VERSION 5.7 ;
  NOWIREEXTENSIONATPIN ON ;
  DIVIDERCHAR "/" ;
  BUSBITCHARS "[]" ;
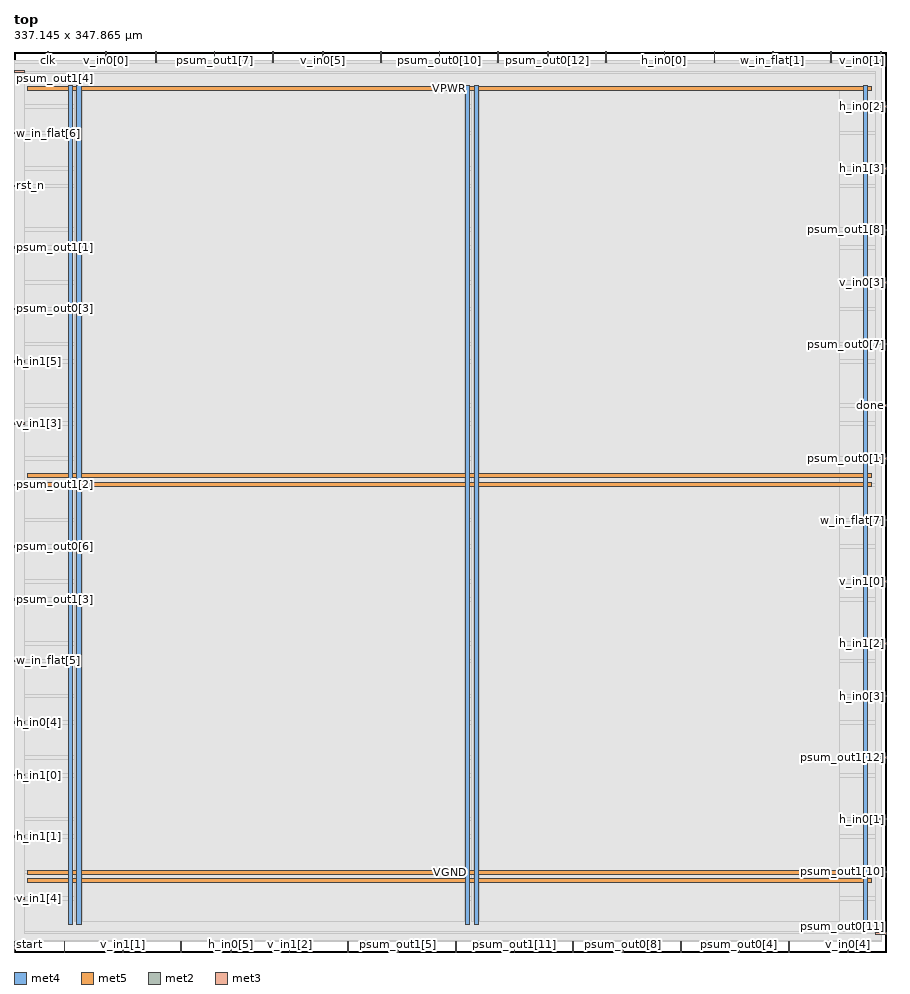
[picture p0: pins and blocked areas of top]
MACRO top
  CLASS BLOCK ;
  FOREIGN top ;
  ORIGIN 0.000 0.000 ;
  SIZE 337.145 BY 347.865 ;
  PIN VGND
    DIRECTION INOUT ;
    USE GROUND ;
    PORT
      LAYER met4 ;
        RECT 24.340 10.640 25.940 334.800 ;
    END
    PORT
      LAYER met4 ;
        RECT 177.940 10.640 179.540 334.800 ;
    END
    PORT
      LAYER met5 ;
        RECT 5.280 30.030 331.440 31.630 ;
    END
    PORT
      LAYER met5 ;
        RECT 5.280 183.210 331.440 184.810 ;
    END
  END VGND
  PIN VPWR
    DIRECTION INOUT ;
    USE POWER ;
    PORT
      LAYER met4 ;
        RECT 21.040 10.640 22.640 334.800 ;
    END
    PORT
      LAYER met4 ;
        RECT 174.640 10.640 176.240 334.800 ;
    END
    PORT
      LAYER met4 ;
        RECT 328.240 10.640 329.840 334.800 ;
    END
    PORT
      LAYER met5 ;
        RECT 5.280 26.730 331.440 28.330 ;
    END
    PORT
      LAYER met5 ;
        RECT 5.280 179.910 331.440 181.510 ;
    END
    PORT
      LAYER met5 ;
        RECT 5.280 333.090 331.440 334.690 ;
    END
  END VPWR
  PIN clk
    DIRECTION INPUT ;
    USE SIGNAL ;
    ANTENNAGATEAREA 0.852000 ;
    PORT
      LAYER met2 ;
        RECT 12.970 343.865 13.250 347.865 ;
    END
  END clk
  PIN done
    DIRECTION OUTPUT TRISTATE ;
    USE SIGNAL ;
    ANTENNADIFFAREA 0.445500 ;
    PORT
      LAYER met3 ;
        RECT 333.145 210.840 337.145 211.440 ;
    END
  END done
  PIN h_in0[0]
    DIRECTION INPUT ;
    USE SIGNAL ;
    ANTENNAGATEAREA 0.213000 ;
    PORT
      LAYER met2 ;
        RECT 251.250 343.865 251.530 347.865 ;
    END
  END h_in0[0]
  PIN h_in0[1]
    DIRECTION INPUT ;
    USE SIGNAL ;
    ANTENNAGATEAREA 0.213000 ;
    PORT
      LAYER met3 ;
        RECT 333.145 51.040 337.145 51.640 ;
    END
  END h_in0[1]
  PIN h_in0[2]
    DIRECTION INPUT ;
    USE SIGNAL ;
    ANTENNAGATEAREA 0.213000 ;
    PORT
      LAYER met3 ;
        RECT 333.145 326.440 337.145 327.040 ;
    END
  END h_in0[2]
  PIN h_in0[3]
    DIRECTION INPUT ;
    USE SIGNAL ;
    ANTENNAGATEAREA 0.213000 ;
    PORT
      LAYER met3 ;
        RECT 333.145 98.640 337.145 99.240 ;
    END
  END h_in0[3]
  PIN h_in0[4]
    DIRECTION INPUT ;
    USE SIGNAL ;
    ANTENNAGATEAREA 0.126000 ;
    PORT
      LAYER met3 ;
        RECT 0.000 88.440 4.000 89.040 ;
    END
  END h_in0[4]
  PIN h_in0[5]
    DIRECTION INPUT ;
    USE SIGNAL ;
    ANTENNAGATEAREA 0.213000 ;
    PORT
      LAYER met2 ;
        RECT 83.810 0.000 84.090 4.000 ;
    END
  END h_in0[5]
  PIN h_in1[0]
    DIRECTION INPUT ;
    USE SIGNAL ;
    ANTENNAGATEAREA 0.196500 ;
    PORT
      LAYER met3 ;
        RECT 0.000 68.040 4.000 68.640 ;
    END
  END h_in1[0]
  PIN h_in1[1]
    DIRECTION INPUT ;
    USE SIGNAL ;
    ANTENNAGATEAREA 0.196500 ;
    PORT
      LAYER met3 ;
        RECT 0.000 44.240 4.000 44.840 ;
    END
  END h_in1[1]
  PIN h_in1[2]
    DIRECTION INPUT ;
    USE SIGNAL ;
    ANTENNAGATEAREA 0.213000 ;
    PORT
      LAYER met3 ;
        RECT 333.145 119.040 337.145 119.640 ;
    END
  END h_in1[2]
  PIN h_in1[3]
    DIRECTION INPUT ;
    USE SIGNAL ;
    ANTENNAGATEAREA 0.159000 ;
    PORT
      LAYER met3 ;
        RECT 333.145 302.640 337.145 303.240 ;
    END
  END h_in1[3]
  PIN h_in1[4]
    DIRECTION INPUT ;
    USE SIGNAL ;
    ANTENNAGATEAREA 0.196500 ;
    PORT
      LAYER met2 ;
        RECT 19.410 0.000 19.690 4.000 ;
    END
  END h_in1[4]
  PIN h_in1[5]
    DIRECTION INPUT ;
    USE SIGNAL ;
    ANTENNAGATEAREA 0.196500 ;
    PORT
      LAYER met3 ;
        RECT 0.000 227.840 4.000 228.440 ;
    END
  END h_in1[5]
  PIN psum_out0[0]
    DIRECTION OUTPUT TRISTATE ;
    USE SIGNAL ;
    ANTENNADIFFAREA 0.795200 ;
    PORT
      LAYER met2 ;
        RECT 64.490 0.000 64.770 4.000 ;
    END
  END psum_out0[0]
  PIN psum_out0[10]
    DIRECTION OUTPUT TRISTATE ;
    USE SIGNAL ;
    ANTENNADIFFAREA 0.795200 ;
    PORT
      LAYER met2 ;
        RECT 164.310 343.865 164.590 347.865 ;
    END
  END psum_out0[10]
  PIN psum_out0[11]
    DIRECTION OUTPUT TRISTATE ;
    USE SIGNAL ;
    ANTENNADIFFAREA 0.445500 ;
    PORT
      LAYER met3 ;
        RECT 333.145 6.840 337.145 7.440 ;
    END
  END psum_out0[11]
  PIN psum_out0[12]
    DIRECTION OUTPUT TRISTATE ;
    USE SIGNAL ;
    ANTENNADIFFAREA 0.795200 ;
    PORT
      LAYER met2 ;
        RECT 206.170 343.865 206.450 347.865 ;
    END
  END psum_out0[12]
  PIN psum_out0[1]
    DIRECTION OUTPUT TRISTATE ;
    USE SIGNAL ;
    ANTENNADIFFAREA 0.445500 ;
    PORT
      LAYER met3 ;
        RECT 333.145 190.440 337.145 191.040 ;
    END
  END psum_out0[1]
  PIN psum_out0[2]
    DIRECTION OUTPUT TRISTATE ;
    USE SIGNAL ;
    ANTENNADIFFAREA 0.795200 ;
    PORT
      LAYER met2 ;
        RECT 141.770 343.865 142.050 347.865 ;
    END
  END psum_out0[2]
  PIN psum_out0[3]
    DIRECTION OUTPUT TRISTATE ;
    USE SIGNAL ;
    ANTENNADIFFAREA 0.795200 ;
    PORT
      LAYER met3 ;
        RECT 0.000 248.240 4.000 248.840 ;
    END
  END psum_out0[3]
  PIN psum_out0[4]
    DIRECTION OUTPUT TRISTATE ;
    USE SIGNAL ;
    ANTENNADIFFAREA 0.795200 ;
    PORT
      LAYER met2 ;
        RECT 280.230 0.000 280.510 4.000 ;
    END
  END psum_out0[4]
  PIN psum_out0[5]
    DIRECTION OUTPUT TRISTATE ;
    USE SIGNAL ;
    ANTENNADIFFAREA 0.795200 ;
    PORT
      LAYER met2 ;
        RECT 257.690 0.000 257.970 4.000 ;
    END
  END psum_out0[5]
  PIN psum_out0[6]
    DIRECTION OUTPUT TRISTATE ;
    USE SIGNAL ;
    ANTENNADIFFAREA 0.795200 ;
    PORT
      LAYER met3 ;
        RECT 0.000 156.440 4.000 157.040 ;
    END
  END psum_out0[6]
  PIN psum_out0[7]
    DIRECTION OUTPUT TRISTATE ;
    USE SIGNAL ;
    ANTENNADIFFAREA 0.795200 ;
    PORT
      LAYER met3 ;
        RECT 333.145 234.640 337.145 235.240 ;
    END
  END psum_out0[7]
  PIN psum_out0[8]
    DIRECTION OUTPUT TRISTATE ;
    USE SIGNAL ;
    ANTENNADIFFAREA 0.795200 ;
    PORT
      LAYER met2 ;
        RECT 235.150 0.000 235.430 4.000 ;
    END
  END psum_out0[8]
  PIN psum_out0[9]
    DIRECTION OUTPUT TRISTATE ;
    USE SIGNAL ;
    ANTENNADIFFAREA 0.795200 ;
    PORT
      LAYER met2 ;
        RECT 228.710 343.865 228.990 347.865 ;
    END
  END psum_out0[9]
  PIN psum_out1[0]
    DIRECTION OUTPUT TRISTATE ;
    USE SIGNAL ;
    ANTENNADIFFAREA 0.795200 ;
    PORT
      LAYER met2 ;
        RECT 299.550 0.000 299.830 4.000 ;
    END
  END psum_out1[0]
  PIN psum_out1[10]
    DIRECTION OUTPUT TRISTATE ;
    USE SIGNAL ;
    ANTENNADIFFAREA 0.445500 ;
    PORT
      LAYER met3 ;
        RECT 333.145 30.640 337.145 31.240 ;
    END
  END psum_out1[10]
  PIN psum_out1[11]
    DIRECTION OUTPUT TRISTATE ;
    USE SIGNAL ;
    ANTENNADIFFAREA 0.795200 ;
    PORT
      LAYER met2 ;
        RECT 193.290 0.000 193.570 4.000 ;
    END
  END psum_out1[11]
  PIN psum_out1[12]
    DIRECTION OUTPUT TRISTATE ;
    USE SIGNAL ;
    ANTENNADIFFAREA 0.795200 ;
    PORT
      LAYER met3 ;
        RECT 333.145 74.840 337.145 75.440 ;
    END
  END psum_out1[12]
  PIN psum_out1[1]
    DIRECTION OUTPUT TRISTATE ;
    USE SIGNAL ;
    ANTENNADIFFAREA 0.795200 ;
    PORT
      LAYER met3 ;
        RECT 0.000 272.040 4.000 272.640 ;
    END
  END psum_out1[1]
  PIN psum_out1[2]
    DIRECTION OUTPUT TRISTATE ;
    USE SIGNAL ;
    ANTENNADIFFAREA 0.795200 ;
    PORT
      LAYER met3 ;
        RECT 0.000 180.240 4.000 180.840 ;
    END
  END psum_out1[2]
  PIN psum_out1[3]
    DIRECTION OUTPUT TRISTATE ;
    USE SIGNAL ;
    ANTENNADIFFAREA 0.795200 ;
    PORT
      LAYER met3 ;
        RECT 0.000 136.040 4.000 136.640 ;
    END
  END psum_out1[3]
  PIN psum_out1[4]
    DIRECTION OUTPUT TRISTATE ;
    USE SIGNAL ;
    ANTENNADIFFAREA 0.795200 ;
    PORT
      LAYER met3 ;
        RECT 0.000 340.040 4.000 340.640 ;
    END
  END psum_out1[4]
  PIN psum_out1[5]
    DIRECTION OUTPUT TRISTATE ;
    USE SIGNAL ;
    ANTENNADIFFAREA 0.445500 ;
    PORT
      LAYER met2 ;
        RECT 148.210 0.000 148.490 4.000 ;
    END
  END psum_out1[5]
  PIN psum_out1[6]
    DIRECTION OUTPUT TRISTATE ;
    USE SIGNAL ;
    ANTENNADIFFAREA 0.795200 ;
    PORT
      LAYER met2 ;
        RECT 270.570 343.865 270.850 347.865 ;
    END
  END psum_out1[6]
  PIN psum_out1[7]
    DIRECTION OUTPUT TRISTATE ;
    USE SIGNAL ;
    ANTENNADIFFAREA 0.795200 ;
    PORT
      LAYER met2 ;
        RECT 77.370 343.865 77.650 347.865 ;
    END
  END psum_out1[7]
  PIN psum_out1[8]
    DIRECTION OUTPUT TRISTATE ;
    USE SIGNAL ;
    ANTENNADIFFAREA 0.445500 ;
    PORT
      LAYER met3 ;
        RECT 333.145 278.840 337.145 279.440 ;
    END
  END psum_out1[8]
  PIN psum_out1[9]
    DIRECTION OUTPUT TRISTATE ;
    USE SIGNAL ;
    ANTENNADIFFAREA 0.795200 ;
    PORT
      LAYER met2 ;
        RECT 186.850 343.865 187.130 347.865 ;
    END
  END psum_out1[9]
  PIN rst_n
    DIRECTION INPUT ;
    USE SIGNAL ;
    ANTENNAGATEAREA 0.990000 ;
    PORT
      LAYER met3 ;
        RECT 0.000 295.840 4.000 296.440 ;
    END
  END rst_n
  PIN start
    DIRECTION INPUT ;
    USE SIGNAL ;
    ANTENNAGATEAREA 0.213000 ;
    PORT
      LAYER met2 ;
        RECT 0.090 0.000 0.370 4.000 ;
    END
  END start
  PIN v_in0[0]
    DIRECTION INPUT ;
    USE SIGNAL ;
    ANTENNAGATEAREA 0.213000 ;
    PORT
      LAYER met2 ;
        RECT 35.510 343.865 35.790 347.865 ;
    END
  END v_in0[0]
  PIN v_in0[1]
    DIRECTION INPUT ;
    USE SIGNAL ;
    ANTENNAGATEAREA 0.159000 ;
    PORT
      LAYER met2 ;
        RECT 334.970 343.865 335.250 347.865 ;
    END
  END v_in0[1]
  PIN v_in0[2]
    DIRECTION INPUT ;
    USE SIGNAL ;
    ANTENNAGATEAREA 0.196500 ;
    PORT
      LAYER met2 ;
        RECT 128.890 0.000 129.170 4.000 ;
    END
  END v_in0[2]
  PIN v_in0[3]
    DIRECTION INPUT ;
    USE SIGNAL ;
    ANTENNAGATEAREA 0.213000 ;
    PORT
      LAYER met3 ;
        RECT 333.145 258.440 337.145 259.040 ;
    END
  END v_in0[3]
  PIN v_in0[4]
    DIRECTION INPUT ;
    USE SIGNAL ;
    ANTENNAGATEAREA 0.213000 ;
    PORT
      LAYER met2 ;
        RECT 322.090 0.000 322.370 4.000 ;
    END
  END v_in0[4]
  PIN v_in0[5]
    DIRECTION INPUT ;
    USE SIGNAL ;
    ANTENNAGATEAREA 0.196500 ;
    PORT
      LAYER met2 ;
        RECT 119.230 343.865 119.510 347.865 ;
    END
  END v_in0[5]
  PIN v_in1[0]
    DIRECTION INPUT ;
    USE SIGNAL ;
    ANTENNAGATEAREA 0.213000 ;
    PORT
      LAYER met3 ;
        RECT 333.145 142.840 337.145 143.440 ;
    END
  END v_in1[0]
  PIN v_in1[1]
    DIRECTION INPUT ;
    USE SIGNAL ;
    ANTENNAGATEAREA 0.196500 ;
    PORT
      LAYER met2 ;
        RECT 41.950 0.000 42.230 4.000 ;
    END
  END v_in1[1]
  PIN v_in1[2]
    DIRECTION INPUT ;
    USE SIGNAL ;
    ANTENNAGATEAREA 0.196500 ;
    PORT
      LAYER met2 ;
        RECT 106.350 0.000 106.630 4.000 ;
    END
  END v_in1[2]
  PIN v_in1[3]
    DIRECTION INPUT ;
    USE SIGNAL ;
    ANTENNAGATEAREA 0.213000 ;
    PORT
      LAYER met3 ;
        RECT 0.000 204.040 4.000 204.640 ;
    END
  END v_in1[3]
  PIN v_in1[4]
    DIRECTION INPUT ;
    USE SIGNAL ;
    ANTENNAGATEAREA 0.196500 ;
    PORT
      LAYER met3 ;
        RECT 0.000 20.440 4.000 21.040 ;
    END
  END v_in1[4]
  PIN v_in1[5]
    DIRECTION INPUT ;
    USE SIGNAL ;
    ANTENNAGATEAREA 0.196500 ;
    PORT
      LAYER met2 ;
        RECT 170.750 0.000 171.030 4.000 ;
    END
  END v_in1[5]
  PIN w_in_flat[0]
    DIRECTION INPUT ;
    USE SIGNAL ;
    ANTENNAGATEAREA 0.196500 ;
    PORT
      LAYER met2 ;
        RECT 315.650 343.865 315.930 347.865 ;
    END
  END w_in_flat[0]
  PIN w_in_flat[1]
    DIRECTION INPUT ;
    USE SIGNAL ;
    ANTENNAGATEAREA 0.196500 ;
    PORT
      LAYER met2 ;
        RECT 293.110 343.865 293.390 347.865 ;
    END
  END w_in_flat[1]
  PIN w_in_flat[2]
    DIRECTION INPUT ;
    USE SIGNAL ;
    ANTENNAGATEAREA 0.196500 ;
    PORT
      LAYER met2 ;
        RECT 54.830 343.865 55.110 347.865 ;
    END
  END w_in_flat[2]
  PIN w_in_flat[3]
    DIRECTION INPUT ;
    USE SIGNAL ;
    ANTENNAGATEAREA 0.196500 ;
    PORT
      LAYER met2 ;
        RECT 99.910 343.865 100.190 347.865 ;
    END
  END w_in_flat[3]
  PIN w_in_flat[4]
    DIRECTION INPUT ;
    USE SIGNAL ;
    ANTENNAGATEAREA 0.196500 ;
    PORT
      LAYER met2 ;
        RECT 215.830 0.000 216.110 4.000 ;
    END
  END w_in_flat[4]
  PIN w_in_flat[5]
    DIRECTION INPUT ;
    USE SIGNAL ;
    ANTENNAGATEAREA 0.196500 ;
    PORT
      LAYER met3 ;
        RECT 0.000 112.240 4.000 112.840 ;
    END
  END w_in_flat[5]
  PIN w_in_flat[6]
    DIRECTION INPUT ;
    USE SIGNAL ;
    ANTENNAGATEAREA 0.196500 ;
    PORT
      LAYER met3 ;
        RECT 0.000 316.240 4.000 316.840 ;
    END
  END w_in_flat[6]
  PIN w_in_flat[7]
    DIRECTION INPUT ;
    USE SIGNAL ;
    ANTENNAGATEAREA 0.196500 ;
    PORT
      LAYER met3 ;
        RECT 333.145 166.640 337.145 167.240 ;
    END
  END w_in_flat[7]
  OBS
      LAYER li1 ;
        RECT 5.520 10.795 331.200 334.645 ;
      LAYER met1 ;
        RECT 0.070 9.900 335.270 334.800 ;
      LAYER met2 ;
        RECT 0.100 343.585 12.690 344.490 ;
        RECT 13.530 343.585 35.230 344.490 ;
        RECT 36.070 343.585 54.550 344.490 ;
        RECT 55.390 343.585 77.090 344.490 ;
        RECT 77.930 343.585 99.630 344.490 ;
        RECT 100.470 343.585 118.950 344.490 ;
        RECT 119.790 343.585 141.490 344.490 ;
        RECT 142.330 343.585 164.030 344.490 ;
        RECT 164.870 343.585 186.570 344.490 ;
        RECT 187.410 343.585 205.890 344.490 ;
        RECT 206.730 343.585 228.430 344.490 ;
        RECT 229.270 343.585 250.970 344.490 ;
        RECT 251.810 343.585 270.290 344.490 ;
        RECT 271.130 343.585 292.830 344.490 ;
        RECT 293.670 343.585 315.370 344.490 ;
        RECT 316.210 343.585 334.690 344.490 ;
        RECT 0.100 4.280 335.240 343.585 ;
        RECT 0.650 4.000 19.130 4.280 ;
        RECT 19.970 4.000 41.670 4.280 ;
        RECT 42.510 4.000 64.210 4.280 ;
        RECT 65.050 4.000 83.530 4.280 ;
        RECT 84.370 4.000 106.070 4.280 ;
        RECT 106.910 4.000 128.610 4.280 ;
        RECT 129.450 4.000 147.930 4.280 ;
        RECT 148.770 4.000 170.470 4.280 ;
        RECT 171.310 4.000 193.010 4.280 ;
        RECT 193.850 4.000 215.550 4.280 ;
        RECT 216.390 4.000 234.870 4.280 ;
        RECT 235.710 4.000 257.410 4.280 ;
        RECT 258.250 4.000 279.950 4.280 ;
        RECT 280.790 4.000 299.270 4.280 ;
        RECT 300.110 4.000 321.810 4.280 ;
        RECT 322.650 4.000 335.240 4.280 ;
      LAYER met3 ;
        RECT 4.400 339.640 333.145 340.490 ;
        RECT 4.000 327.440 333.145 339.640 ;
        RECT 4.000 326.040 332.745 327.440 ;
        RECT 4.000 317.240 333.145 326.040 ;
        RECT 4.400 315.840 333.145 317.240 ;
        RECT 4.000 303.640 333.145 315.840 ;
        RECT 4.000 302.240 332.745 303.640 ;
        RECT 4.000 296.840 333.145 302.240 ;
        RECT 4.400 295.440 333.145 296.840 ;
        RECT 4.000 279.840 333.145 295.440 ;
        RECT 4.000 278.440 332.745 279.840 ;
        RECT 4.000 273.040 333.145 278.440 ;
        RECT 4.400 271.640 333.145 273.040 ;
        RECT 4.000 259.440 333.145 271.640 ;
        RECT 4.000 258.040 332.745 259.440 ;
        RECT 4.000 249.240 333.145 258.040 ;
        RECT 4.400 247.840 333.145 249.240 ;
        RECT 4.000 235.640 333.145 247.840 ;
        RECT 4.000 234.240 332.745 235.640 ;
        RECT 4.000 228.840 333.145 234.240 ;
        RECT 4.400 227.440 333.145 228.840 ;
        RECT 4.000 211.840 333.145 227.440 ;
        RECT 4.000 210.440 332.745 211.840 ;
        RECT 4.000 205.040 333.145 210.440 ;
        RECT 4.400 203.640 333.145 205.040 ;
        RECT 4.000 191.440 333.145 203.640 ;
        RECT 4.000 190.040 332.745 191.440 ;
        RECT 4.000 181.240 333.145 190.040 ;
        RECT 4.400 179.840 333.145 181.240 ;
        RECT 4.000 167.640 333.145 179.840 ;
        RECT 4.000 166.240 332.745 167.640 ;
        RECT 4.000 157.440 333.145 166.240 ;
        RECT 4.400 156.040 333.145 157.440 ;
        RECT 4.000 143.840 333.145 156.040 ;
        RECT 4.000 142.440 332.745 143.840 ;
        RECT 4.000 137.040 333.145 142.440 ;
        RECT 4.400 135.640 333.145 137.040 ;
        RECT 4.000 120.040 333.145 135.640 ;
        RECT 4.000 118.640 332.745 120.040 ;
        RECT 4.000 113.240 333.145 118.640 ;
        RECT 4.400 111.840 333.145 113.240 ;
        RECT 4.000 99.640 333.145 111.840 ;
        RECT 4.000 98.240 332.745 99.640 ;
        RECT 4.000 89.440 333.145 98.240 ;
        RECT 4.400 88.040 333.145 89.440 ;
        RECT 4.000 75.840 333.145 88.040 ;
        RECT 4.000 74.440 332.745 75.840 ;
        RECT 4.000 69.040 333.145 74.440 ;
        RECT 4.400 67.640 333.145 69.040 ;
        RECT 4.000 52.040 333.145 67.640 ;
        RECT 4.000 50.640 332.745 52.040 ;
        RECT 4.000 45.240 333.145 50.640 ;
        RECT 4.400 43.840 333.145 45.240 ;
        RECT 4.000 31.640 333.145 43.840 ;
        RECT 4.000 30.240 332.745 31.640 ;
        RECT 4.000 21.440 333.145 30.240 ;
        RECT 4.400 20.040 333.145 21.440 ;
        RECT 4.000 7.840 333.145 20.040 ;
        RECT 4.000 6.975 332.745 7.840 ;
      LAYER met4 ;
        RECT 23.295 11.735 23.940 333.025 ;
        RECT 26.340 11.735 174.240 333.025 ;
        RECT 176.640 11.735 177.540 333.025 ;
        RECT 179.940 11.735 318.945 333.025 ;
  END
END top
END LIBRARY

